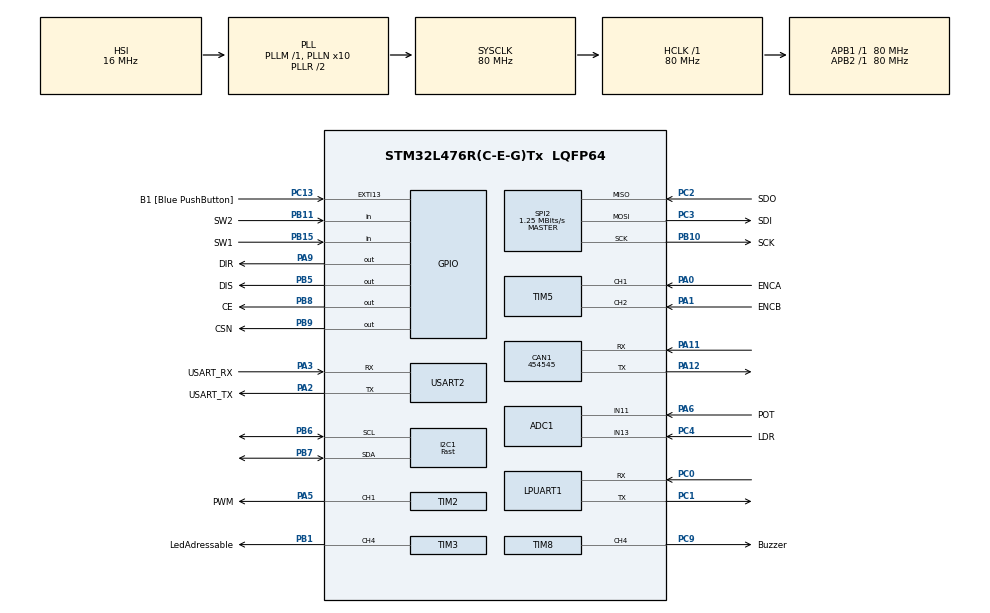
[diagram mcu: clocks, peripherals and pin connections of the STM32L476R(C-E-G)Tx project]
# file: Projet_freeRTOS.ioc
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ADC1.Channel-0\#ChannelRegularConversion=ADC_CHANNEL_11
ADC1.Channel-1\#ChannelRegularConversion=ADC_CHANNEL_13
ADC1.EOCSelection=ADC_EOC_SINGLE_CONV
ADC1.NbrOfConversion=2
ADC1.NbrOfConversionFlag=1
ADC1.OffsetNumber-0\#ChannelRegularConversion=ADC_OFFSET_NONE
ADC1.OffsetNumber-1\#ChannelRegularConversion=ADC_OFFSET_NONE
ADC1.Rank-0\#ChannelRegularConversion=1
ADC1.Rank-1\#ChannelRegularConversion=2
ADC1.SamplingTime-0\#ChannelRegularConversion=ADC_SAMPLETIME_47CYCLES_5
ADC1.SamplingTime-1\#ChannelRegularConversion=ADC_SAMPLETIME_47CYCLES_5
ADC1.master=1
CAN1.BS1=CAN_BS1_6TQ
CAN1.BS2=CAN_BS2_4TQ
CAN1.CalculateBaudRate=454545
CAN1.CalculateTimeBit=2200
CAN1.CalculateTimeQuantum=200.0
Dma.Request0=TIM3_CH4/UP
Dma.TIM3_CH4/UP.0.Direction=DMA_MEMORY_TO_PERIPH
Dma.TIM3_CH4/UP.0.Instance=DMA1_Channel3
Dma.TIM3_CH4/UP.0.MemDataAlignment=DMA_MDATAALIGN_HALFWORD
Dma.TIM3_CH4/UP.0.MemInc=DMA_MINC_ENABLE
Dma.TIM3_CH4/UP.0.Mode=DMA_NORMAL
Dma.TIM3_CH4/UP.0.PeriphDataAlignment=DMA_PDATAALIGN_HALFWORD
Dma.TIM3_CH4/UP.0.PeriphInc=DMA_PINC_DISABLE
Dma.TIM3_CH4/UP.0.Priority=DMA_PRIORITY_LOW
FREERTOS.INCLUDE_vTaskDelayUntil=1
FREERTOS.Tasks01=defaultTask,0,128,StartDefaultTask,Default,NULL,Dynamic,NULL,NULL
FREERTOS.configMAX_PRIORITIES=16
FREERTOS.configTOTAL_HEAP_SIZE=35000
FREERTOS.configUSE_IDLE_HOOK=1
FREERTOS.configUSE_NEWLIB_REENTRANT=1
I2C1.I2C_Speed_Mode=I2C_Fast
I2C1.Timing=0x00F12981
Mcu.Family=STM32L4
Mcu.Name=STM32L476R(C-E-G)Tx
Mcu.Package=LQFP64
NVIC.ADC1_2_IRQn=true\:5\:0\:false\:false\:true\:true\:true\:true\:true
NVIC.DMA1_Channel3_IRQn=true\:5\:0\:false\:false\:true\:true\:false\:true\:true
NVIC.PriorityGroup=NVIC_PRIORITYGROUP_4
NVIC.TIM6_DAC_IRQn=true\:15\:0\:false\:false\:true\:false\:false\:true\:true
NVIC.TimeBase=TIM6_DAC_IRQn
NVIC.TimeBaseIP=TIM6
PA0.GPIO_Label=ENCA
PA0.Signal=S_TIM5_CH1
PA1.GPIO_Label=ENCB
PA1.Signal=S_TIM5_CH2
PA11.Mode=CAN_Activate
PA11.Signal=CAN1_RX
PA12.Mode=CAN_Activate
PA12.Signal=CAN1_TX
PA13\ (JTMS-SWDIO).GPIO_Label=TMS
PA13\ (JTMS-SWDIO).Mode=Serial_Wire
PA13\ (JTMS-SWDIO).Signal=SYS_JTMS-SWDIO
PA14\ (JTCK-SWCLK).GPIO_Label=TCK
PA14\ (JTCK-SWCLK).Mode=Serial_Wire
PA14\ (JTCK-SWCLK).Signal=SYS_JTCK-SWCLK
PA2.GPIO_Label=USART_TX
PA2.GPIO_Mode=GPIO_MODE_AF_PP
PA2.GPIO_PuPd=GPIO_NOPULL
PA2.GPIO_Speed=GPIO_SPEED_FREQ_VERY_HIGH
PA2.Mode=Asynchronous
PA2.Signal=USART2_TX
PA3.GPIO_Label=USART_RX
PA3.GPIO_Mode=GPIO_MODE_AF_PP
PA3.GPIO_PuPd=GPIO_NOPULL
PA3.GPIO_Speed=GPIO_SPEED_FREQ_VERY_HIGH
PA3.Mode=Asynchronous
PA3.Signal=USART2_RX
PA5.GPIO_Label=PWM
PA5.Signal=S_TIM2_CH1
PA6.GPIO_Label=POT
PA6.Signal=ADCx_IN11
PA9.GPIO_Label=DIR
PA9.Signal=GPIO_Output
PB1.GPIO_Label=LedAdressable
PB1.Signal=S_TIM3_CH4
PB10.GPIO_Label=SCK
PB10.Mode=Full_Duplex_Master
PB10.Signal=SPI2_SCK
PB11.GPIO_Label=SW2
PB11.Signal=GPIO_Input
PB15.GPIO_Label=SW1
PB15.Signal=GPIO_Input
PB3\ (JTDO-TRACESWO).GPIO_Label=SWO
PB3\ (JTDO-TRACESWO).Signal=SYS_JTDO-SWO
PB5.GPIO_Label=DIS
PB5.Signal=GPIO_Output
PB6.Mode=I2C
PB6.Signal=I2C1_SCL
PB7.Mode=I2C
PB7.Signal=I2C1_SDA
PB8.GPIO_Label=CE
PB8.Signal=GPIO_Output
PB9.GPIO_Label=CSN
PB9.Signal=GPIO_Output
PC0.Mode=Asynchronous
PC0.Signal=LPUART1_RX
PC1.Mode=Asynchronous
PC1.Signal=LPUART1_TX
PC13.GPIO_Label=B1 [Blue PushButton]
PC13.GPIO_ModeDefaultEXTI=GPIO_MODE_IT_FALLING
PC13.GPIO_PuPd=GPIO_NOPULL
PC13.Signal=GPXTI13
PC14-OSC32_IN\ (PC14).Mode=LSE-External-Oscillator
PC14-OSC32_IN\ (PC14).Signal=RCC_OSC32_IN
PC15-OSC32_OUT\ (PC15).Mode=LSE-External-Oscillator
PC15-OSC32_OUT\ (PC15).Signal=RCC_OSC32_OUT
PC2.GPIO_Label=SDO
PC2.Mode=Full_Duplex_Master
PC2.Signal=SPI2_MISO
PC3.GPIO_Label=SDI
PC3.Mode=Full_Duplex_Master
PC3.Signal=SPI2_MOSI
PC4.GPIO_Label=LDR
PC4.Signal=ADCx_IN13
PC9.GPIO_Label=Buzzer
PC9.Signal=S_TIM8_CH4
PH0-OSC_IN\ (PH0).Signal=RCC_OSC_IN
PH1-OSC_OUT\ (PH1).Signal=RCC_OSC_OUT
ProjectManager.HeapSize=0x200
ProjectManager.StackSize=0x400
ProjectManager.TargetToolchain=STM32CubeIDE
RCC.ADCFreq_Value=64000000
RCC.AHBFreq_Value=80000000
RCC.APB1Freq_Value=80000000
RCC.APB1TimFreq_Value=80000000
RCC.APB2Freq_Value=80000000
RCC.APB2TimFreq_Value=80000000
RCC.CortexFreq_Value=80000000
RCC.HCLKFreq_Value=80000000
RCC.HSE_VALUE=8000000
RCC.HSI_VALUE=16000000
RCC.MSI_VALUE=4000000
RCC.PLLN=10
RCC.PLLSourceVirtual=RCC_PLLSOURCE_HSI
RCC.PREFETCH_ENABLE=1
RCC.SYSCLKFreq_VALUE=80000000
RCC.SYSCLKSource=RCC_SYSCLKSOURCE_PLLCLK
RCC.USBFreq_Value=64000000
RCC.VCOOutputFreq_Value=160000000
SH.ADCx_IN11.0=ADC1_IN11,IN11-Single-Ended
SH.ADCx_IN13.0=ADC1_IN13,IN13-Single-Ended
SH.S_TIM2_CH1.0=TIM2_CH1,PWM Generation1 CH1
SH.S_TIM3_CH4.0=TIM3_CH4,PWM Generation4 CH4
SH.S_TIM5_CH1.0=TIM5_CH1,Encoder_Interface
SH.S_TIM5_CH2.0=TIM5_CH2,Encoder_Interface
SH.S_TIM8_CH4.0=TIM8_CH4,PWM Generation4 CH4
SPI2.BaudRatePrescaler=SPI_BAUDRATEPRESCALER_64
SPI2.CLKPhase=SPI_PHASE_2EDGE
SPI2.CalculateBaudRate=1.25 MBits/s
SPI2.DataSize=SPI_DATASIZE_8BIT
SPI2.Direction=SPI_DIRECTION_2LINES
SPI2.Mode=SPI_MODE_MASTER
SPI2.VirtualType=VM_MASTER
TIM2.Channel-PWM\ Generation1\ CH1=TIM_CHANNEL_1
TIM2.Period=3999
TIM3.Channel-PWM\ Generation4\ CH4=TIM_CHANNEL_4
TIM3.Period=99
TIM5.EncoderMode=TIM_ENCODERMODE_TI12
TIM8.Channel-PWM\ Generation4\ CH4=TIM_CHANNEL_4
TIM8.Period=65535
TIM8.Prescaler=79
USART2.VirtualMode-Asynchronous=VM_ASYNC
VP_FREERTOS_VS_CMSIS_V1.Mode=CMSIS_V1
VP_SYS_VS_tim6.Mode=TIM6
VP_TIM3_VS_ClockSourceINT.Mode=Internal
VP_TIM8_VS_ClockSourceINT.Mode=Internal
board=NUCLEO-L476RG

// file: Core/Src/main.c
/* USER CODE BEGIN Header */
/**
 ******************************************************************************
 * @file           : main.c
 * @brief          : Main program body
 ******************************************************************************
 * @attention
 *
 * Copyright (c) 2026 STMicroelectronics.
 * All rights reserved.
 *
 * This software is licensed under terms that can be found in the LICENSE file
 * in the root directory of this software component.
 * If no LICENSE file comes with this software, it is provided AS-IS.
 *
 ******************************************************************************
 */
/* USER CODE END Header */
#include "main.h"
#include "cmsis_os.h"

/* USER CODE BEGIN Includes */
#include <stdio.h>
#include <stdlib.h>
#include "ssd1306.h"
#include <stdbool.h>

#include <string.h>
#include "vl53l1_api.h"

#include "ssd1306_fonts.h"
#include "app_rtos.h"
/* USER CODE END Includes */

ADC_HandleTypeDef hadc1;

CAN_HandleTypeDef hcan1;

I2C_HandleTypeDef hi2c1;

UART_HandleTypeDef hlpuart1;
UART_HandleTypeDef huart2;

SPI_HandleTypeDef hspi2;

TIM_HandleTypeDef htim2;
TIM_HandleTypeDef htim3;
TIM_HandleTypeDef htim5;
TIM_HandleTypeDef htim8;
DMA_HandleTypeDef hdma_tim3_ch4_up;

osThreadId defaultTaskHandle;

void SystemClock_Config(void);
static void MX_GPIO_Init(void);
static void MX_DMA_Init(void);
static void MX_USART2_UART_Init(void);
static void MX_I2C1_Init(void);
static void MX_ADC1_Init(void);
static void MX_CAN1_Init(void);
static void MX_LPUART1_UART_Init(void);
static void MX_SPI2_Init(void);
static void MX_TIM2_Init(void);
static void MX_TIM3_Init(void);
static void MX_TIM5_Init(void);
static void MX_TIM8_Init(void);
void StartDefaultTask(void const * argument);

int main(void)
{

	/* MCU Configuration--------------------------------------------------------*/

	/* Reset of all peripherals, Initializes the Flash interface and the Systick. */
	HAL_Init();

	/* Configure the system clock */
	SystemClock_Config();

	/* Initialize all configured peripherals */
	MX_GPIO_Init();
	MX_DMA_Init();
	MX_USART2_UART_Init();
	MX_I2C1_Init();
	MX_ADC1_Init();
	MX_CAN1_Init();
	MX_LPUART1_UART_Init();
	MX_SPI2_Init();
	MX_TIM2_Init();
	MX_TIM3_Init();
	MX_TIM5_Init();
	MX_TIM8_Init();
	/* USER CODE BEGIN 2 */

	HAL_ADCEx_Calibration_Start(&hadc1, ADC_SINGLE_ENDED);
	HAL_TIM_PWM_Start(&htim2, TIM_CHANNEL_1);                   // Lancement ventilateur (PA5)
	HAL_TIM_Encoder_Start(&htim5, TIM_CHANNEL_ALL);             // Lancement encodeur
	HAL_GPIO_WritePin(DIS_GPIO_Port, DIS_Pin, GPIO_PIN_SET);    // moteur désactivé au départ
	// moteur désactivé au départ
	HAL_UART_Receive_IT(&hlpuart1, (uint8_t *) &bluetoothChar, 1);

	//seuils de base
	consignes.seuil_temperature = 25;
	consignes.seuil_qa = 100;
	consignes.seuil_luminosite = 500;
	/* USER CODE END 2 */

	/* Create the thread(s) */
	/* definition and creation of defaultTask */
	osThreadDef(defaultTask, StartDefaultTask, osPriorityNormal, 0, 128);
	defaultTaskHandle = osThreadCreate(osThread(defaultTask), NULL);

	/* USER CODE BEGIN RTOS_THREADS */
	App_init();  // création des tâches (app_rtos.c)
	/* USER CODE END RTOS_THREADS */

	/* Start scheduler */
	osKernelStart();

	/* We should never get here as control is now taken by the scheduler */

	/* Infinite loop */
	while (1)
	{

	}
}

void SystemClock_Config(void)
{
	RCC_OscInitTypeDef RCC_OscInitStruct = {0};
	RCC_ClkInitTypeDef RCC_ClkInitStruct = {0};

	/** Configure the main internal regulator output voltage
	 */
	if (HAL_PWREx_ControlVoltageScaling(PWR_REGULATOR_VOLTAGE_SCALE1) != HAL_OK)
	{
		Error_Handler();
	}

	/** Initializes the RCC Oscillators according to the specified parameters
	 * in the RCC_OscInitTypeDef structure.
	 */
	RCC_OscInitStruct.OscillatorType = RCC_OSCILLATORTYPE_HSI;
	RCC_OscInitStruct.HSIState = RCC_HSI_ON;
	RCC_OscInitStruct.HSICalibrationValue = RCC_HSICALIBRATION_DEFAULT;
	RCC_OscInitStruct.PLL.PLLState = RCC_PLL_ON;
	RCC_OscInitStruct.PLL.PLLSource = RCC_PLLSOURCE_HSI;
	RCC_OscInitStruct.PLL.PLLM = 1;
	RCC_OscInitStruct.PLL.PLLN = 10;
	RCC_OscInitStruct.PLL.PLLP = RCC_PLLP_DIV7;
	RCC_OscInitStruct.PLL.PLLQ = RCC_PLLQ_DIV2;
	RCC_OscInitStruct.PLL.PLLR = RCC_PLLR_DIV2;
	if (HAL_RCC_OscConfig(&RCC_OscInitStruct) != HAL_OK)
	{
		Error_Handler();
	}

	/** Initializes the CPU, AHB and APB buses clocks
	 */
	RCC_ClkInitStruct.ClockType = RCC_CLOCKTYPE_HCLK|RCC_CLOCKTYPE_SYSCLK
			|RCC_CLOCKTYPE_PCLK1|RCC_CLOCKTYPE_PCLK2;
	RCC_ClkInitStruct.SYSCLKSource = RCC_SYSCLKSOURCE_PLLCLK;
	RCC_ClkInitStruct.AHBCLKDivider = RCC_SYSCLK_DIV1;
	RCC_ClkInitStruct.APB1CLKDivider = RCC_HCLK_DIV1;
	RCC_ClkInitStruct.APB2CLKDivider = RCC_HCLK_DIV1;

	if (HAL_RCC_ClockConfig(&RCC_ClkInitStruct, FLASH_LATENCY_4) != HAL_OK)
	{
		Error_Handler();
	}
}

static void MX_ADC1_Init(void)
{

	ADC_MultiModeTypeDef multimode = {0};
	ADC_ChannelConfTypeDef sConfig = {0};

	/** Common config
	 */
	hadc1.Instance = ADC1;
	hadc1.Init.ClockPrescaler = ADC_CLOCK_ASYNC_DIV1;
	hadc1.Init.Resolution = ADC_RESOLUTION_12B;
	hadc1.Init.DataAlign = ADC_DATAALIGN_RIGHT;
	hadc1.Init.ScanConvMode = ADC_SCAN_DISABLE;
	hadc1.Init.EOCSelection = ADC_EOC_SINGLE_CONV;
	hadc1.Init.LowPowerAutoWait = DISABLE;
	hadc1.Init.ContinuousConvMode = DISABLE;
	hadc1.Init.NbrOfConversion = 1;
	hadc1.Init.DiscontinuousConvMode = DISABLE;
	hadc1.Init.ExternalTrigConv = ADC_SOFTWARE_START;
	hadc1.Init.ExternalTrigConvEdge = ADC_EXTERNALTRIGCONVEDGE_NONE;
	hadc1.Init.DMAContinuousRequests = DISABLE;
	hadc1.Init.Overrun = ADC_OVR_DATA_PRESERVED;
	hadc1.Init.OversamplingMode = DISABLE;
	if (HAL_ADC_Init(&hadc1) != HAL_OK)
	{
		Error_Handler();
	}

	/** Configure the ADC multi-mode
	 */
	multimode.Mode = ADC_MODE_INDEPENDENT;
	if (HAL_ADCEx_MultiModeConfigChannel(&hadc1, &multimode) != HAL_OK)
	{
		Error_Handler();
	}

	/** Configure Regular Channel
	 */
	sConfig.Channel = ADC_CHANNEL_13;
	sConfig.Rank = ADC_REGULAR_RANK_1;
	sConfig.SamplingTime = ADC_SAMPLETIME_2CYCLES_5;
	sConfig.SingleDiff = ADC_SINGLE_ENDED;
	sConfig.OffsetNumber = ADC_OFFSET_NONE;
	sConfig.Offset = 0;
	if (HAL_ADC_ConfigChannel(&hadc1, &sConfig) != HAL_OK)
	{
		Error_Handler();
	}

}

static void MX_CAN1_Init(void)
{

	hcan1.Instance = CAN1;
	hcan1.Init.Prescaler = 16;
	hcan1.Init.Mode = CAN_MODE_NORMAL;
	hcan1.Init.SyncJumpWidth = CAN_SJW_1TQ;
	hcan1.Init.TimeSeg1 = CAN_BS1_7TQ;
	hcan1.Init.TimeSeg2 = CAN_BS2_2TQ;
	hcan1.Init.TimeTriggeredMode = DISABLE;
	hcan1.Init.AutoBusOff = DISABLE;
	hcan1.Init.AutoWakeUp = DISABLE;
	hcan1.Init.AutoRetransmission = DISABLE;
	hcan1.Init.ReceiveFifoLocked = DISABLE;
	hcan1.Init.TransmitFifoPriority = DISABLE;
	if (HAL_CAN_Init(&hcan1) != HAL_OK)
	{
		Error_Handler();
	}

}

static void MX_I2C1_Init(void)
{

	hi2c1.Instance = I2C1;
	hi2c1.Init.Timing = 0x00F12981;
	hi2c1.Init.OwnAddress1 = 0;
	hi2c1.Init.AddressingMode = I2C_ADDRESSINGMODE_7BIT;
	hi2c1.Init.DualAddressMode = I2C_DUALADDRESS_DISABLE;
	hi2c1.Init.OwnAddress2 = 0;
	hi2c1.Init.OwnAddress2Masks = I2C_OA2_NOMASK;
	hi2c1.Init.GeneralCallMode = I2C_GENERALCALL_DISABLE;
	hi2c1.Init.NoStretchMode = I2C_NOSTRETCH_DISABLE;
	if (HAL_I2C_Init(&hi2c1) != HAL_OK)
	{
		Error_Handler();
	}

	/** Configure Analogue filter
	 */
	if (HAL_I2CEx_ConfigAnalogFilter(&hi2c1, I2C_ANALOGFILTER_ENABLE) != HAL_OK)
	{
		Error_Handler();
	}

	/** Configure Digital filter
	 */
	if (HAL_I2CEx_ConfigDigitalFilter(&hi2c1, 0) != HAL_OK)
	{
		Error_Handler();
	}

}

static void MX_LPUART1_UART_Init(void)
{

	hlpuart1.Instance = LPUART1;
	hlpuart1.Init.BaudRate = 9600;
	hlpuart1.Init.WordLength = UART_WORDLENGTH_8B;
	hlpuart1.Init.StopBits = UART_STOPBITS_1;
	hlpuart1.Init.Parity = UART_PARITY_NONE;
	hlpuart1.Init.Mode = UART_MODE_TX_RX;
	hlpuart1.Init.HwFlowCtl = UART_HWCONTROL_NONE;
	hlpuart1.Init.OneBitSampling = UART_ONE_BIT_SAMPLE_DISABLE;
	hlpuart1.AdvancedInit.AdvFeatureInit = UART_ADVFEATURE_NO_INIT;
	if (HAL_UART_Init(&hlpuart1) != HAL_OK)
	{
		Error_Handler();
	}

}

static void MX_USART2_UART_Init(void)
{

	huart2.Instance = USART2;
	huart2.Init.BaudRate = 115200;
	huart2.Init.WordLength = UART_WORDLENGTH_8B;
	huart2.Init.StopBits = UART_STOPBITS_1;
	huart2.Init.Parity = UART_PARITY_NONE;
	huart2.Init.Mode = UART_MODE_TX_RX;
	huart2.Init.HwFlowCtl = UART_HWCONTROL_NONE;
	huart2.Init.OverSampling = UART_OVERSAMPLING_16;
	huart2.Init.OneBitSampling = UART_ONE_BIT_SAMPLE_DISABLE;
	huart2.AdvancedInit.AdvFeatureInit = UART_ADVFEATURE_NO_INIT;
	if (HAL_UART_Init(&huart2) != HAL_OK)
	{
		Error_Handler();
	}

}

static void MX_SPI2_Init(void)
{

	/* SPI2 parameter configuration*/
	hspi2.Instance = SPI2;
	hspi2.Init.Mode = SPI_MODE_MASTER;
	hspi2.Init.Direction = SPI_DIRECTION_2LINES;
	hspi2.Init.DataSize = SPI_DATASIZE_8BIT;
	hspi2.Init.CLKPolarity = SPI_POLARITY_LOW;
	hspi2.Init.CLKPhase = SPI_PHASE_2EDGE;
	hspi2.Init.NSS = SPI_NSS_SOFT;
	hspi2.Init.BaudRatePrescaler = SPI_BAUDRATEPRESCALER_64;
	hspi2.Init.FirstBit = SPI_FIRSTBIT_MSB;
	hspi2.Init.TIMode = SPI_TIMODE_DISABLE;
	hspi2.Init.CRCCalculation = SPI_CRCCALCULATION_DISABLE;
	hspi2.Init.CRCPolynomial = 7;
	hspi2.Init.CRCLength = SPI_CRC_LENGTH_DATASIZE;
	hspi2.Init.NSSPMode = SPI_NSS_PULSE_DISABLE;
	if (HAL_SPI_Init(&hspi2) != HAL_OK)
	{
		Error_Handler();
	}

}

static void MX_TIM2_Init(void)
{

	TIM_MasterConfigTypeDef sMasterConfig = {0};
	TIM_OC_InitTypeDef sConfigOC = {0};

	htim2.Instance = TIM2;
	htim2.Init.Prescaler = 0;
	htim2.Init.CounterMode = TIM_COUNTERMODE_UP;
	htim2.Init.Period = 3999;
	htim2.Init.ClockDivision = TIM_CLOCKDIVISION_DIV1;
	htim2.Init.AutoReloadPreload = TIM_AUTORELOAD_PRELOAD_DISABLE;
	if (HAL_TIM_PWM_Init(&htim2) != HAL_OK)
	{
		Error_Handler();
	}
	sMasterConfig.MasterOutputTrigger = TIM_TRGO_RESET;
	sMasterConfig.MasterSlaveMode = TIM_MASTERSLAVEMODE_DISABLE;
	if (HAL_TIMEx_MasterConfigSynchronization(&htim2, &sMasterConfig) != HAL_OK)
	{
		Error_Handler();
	}
	sConfigOC.OCMode = TIM_OCMODE_PWM1;
	sConfigOC.Pulse = 0;
	sConfigOC.OCPolarity = TIM_OCPOLARITY_HIGH;
	sConfigOC.OCFastMode = TIM_OCFAST_DISABLE;
	if (HAL_TIM_PWM_ConfigChannel(&htim2, &sConfigOC, TIM_CHANNEL_1) != HAL_OK)
	{
		Error_Handler();
	}
	HAL_TIM_MspPostInit(&htim2);

}

static void MX_TIM3_Init(void)
{

	TIM_ClockConfigTypeDef sClockSourceConfig = {0};
	TIM_MasterConfigTypeDef sMasterConfig = {0};
	TIM_OC_InitTypeDef sConfigOC = {0};

	htim3.Instance = TIM3;
	htim3.Init.Prescaler = 0;
	htim3.Init.CounterMode = TIM_COUNTERMODE_UP;
	htim3.Init.Period = 99;
	htim3.Init.ClockDivision = TIM_CLOCKDIVISION_DIV1;
	htim3.Init.AutoReloadPreload = TIM_AUTORELOAD_PRELOAD_DISABLE;
	if (HAL_TIM_Base_Init(&htim3) != HAL_OK)
	{
		Error_Handler();
	}
	sClockSourceConfig.ClockSource = TIM_CLOCKSOURCE_INTERNAL;
	if (HAL_TIM_ConfigClockSource(&htim3, &sClockSourceConfig) != HAL_OK)
	{
		Error_Handler();
	}
	if (HAL_TIM_PWM_Init(&htim3) != HAL_OK)
	{
		Error_Handler();
	}
	sMasterConfig.MasterOutputTrigger = TIM_TRGO_RESET;
	sMasterConfig.MasterSlaveMode = TIM_MASTERSLAVEMODE_DISABLE;
	if (HAL_TIMEx_MasterConfigSynchronization(&htim3, &sMasterConfig) != HAL_OK)
	{
		Error_Handler();
	}
	sConfigOC.OCMode = TIM_OCMODE_PWM1;
	sConfigOC.Pulse = 0;
	sConfigOC.OCPolarity = TIM_OCPOLARITY_HIGH;
	sConfigOC.OCFastMode = TIM_OCFAST_DISABLE;
	if (HAL_TIM_PWM_ConfigChannel(&htim3, &sConfigOC, TIM_CHANNEL_4) != HAL_OK)
	{
		Error_Handler();
	}
	HAL_TIM_MspPostInit(&htim3);

}

static void MX_TIM5_Init(void)
{

	TIM_Encoder_InitTypeDef sConfig = {0};
	TIM_MasterConfigTypeDef sMasterConfig = {0};

	htim5.Instance = TIM5;
	htim5.Init.Prescaler = 0;
	htim5.Init.CounterMode = TIM_COUNTERMODE_UP;
	htim5.Init.Period = 4294967295;
	htim5.Init.ClockDivision = TIM_CLOCKDIVISION_DIV1;
	htim5.Init.AutoReloadPreload = TIM_AUTORELOAD_PRELOAD_DISABLE;
	sConfig.EncoderMode = TIM_ENCODERMODE_TI1;
	sConfig.IC1Polarity = TIM_ICPOLARITY_RISING;
	sConfig.IC1Selection = TIM_ICSELECTION_DIRECTTI;
	sConfig.IC1Prescaler = TIM_ICPSC_DIV1;
	sConfig.IC1Filter = 0;
	sConfig.IC2Polarity = TIM_ICPOLARITY_RISING;
	sConfig.IC2Selection = TIM_ICSELECTION_DIRECTTI;
	sConfig.IC2Prescaler = TIM_ICPSC_DIV1;
	sConfig.IC2Filter = 0;
	if (HAL_TIM_Encoder_Init(&htim5, &sConfig) != HAL_OK)
	{
		Error_Handler();
	}
	sMasterConfig.MasterOutputTrigger = TIM_TRGO_RESET;
	sMasterConfig.MasterSlaveMode = TIM_MASTERSLAVEMODE_DISABLE;
	if (HAL_TIMEx_MasterConfigSynchronization(&htim5, &sMasterConfig) != HAL_OK)
	{
		Error_Handler();
	}

}

static void MX_TIM8_Init(void)
{

	TIM_ClockConfigTypeDef sClockSourceConfig = {0};
	TIM_MasterConfigTypeDef sMasterConfig = {0};
	TIM_OC_InitTypeDef sConfigOC = {0};
	TIM_BreakDeadTimeConfigTypeDef sBreakDeadTimeConfig = {0};

	htim8.Instance = TIM8;
	htim8.Init.Prescaler = 79;
	htim8.Init.CounterMode = TIM_COUNTERMODE_UP;
	htim8.Init.Period = 65535;
	htim8.Init.ClockDivision = TIM_CLOCKDIVISION_DIV1;
	htim8.Init.RepetitionCounter = 0;
	htim8.Init.AutoReloadPreload = TIM_AUTORELOAD_PRELOAD_DISABLE;
	if (HAL_TIM_Base_Init(&htim8) != HAL_OK)
	{
		Error_Handler();
	}
	sClockSourceConfig.ClockSource = TIM_CLOCKSOURCE_INTERNAL;
	if (HAL_TIM_ConfigClockSource(&htim8, &sClockSourceConfig) != HAL_OK)
	{
		Error_Handler();
	}
	if (HAL_TIM_PWM_Init(&htim8) != HAL_OK)
	{
		Error_Handler();
	}
	sMasterConfig.MasterOutputTrigger = TIM_TRGO_RESET;
	sMasterConfig.MasterOutputTrigger2 = TIM_TRGO2_RESET;
	sMasterConfig.MasterSlaveMode = TIM_MASTERSLAVEMODE_DISABLE;
	if (HAL_TIMEx_MasterConfigSynchronization(&htim8, &sMasterConfig) != HAL_OK)
	{
		Error_Handler();
	}
	sConfigOC.OCMode = TIM_OCMODE_PWM1;
	sConfigOC.Pulse = 0;
	sConfigOC.OCPolarity = TIM_OCPOLARITY_HIGH;
	sConfigOC.OCFastMode = TIM_OCFAST_DISABLE;
	sConfigOC.OCIdleState = TIM_OCIDLESTATE_RESET;
	sConfigOC.OCNIdleState = TIM_OCNIDLESTATE_RESET;
	if (HAL_TIM_PWM_ConfigChannel(&htim8, &sConfigOC, TIM_CHANNEL_4) != HAL_OK)
	{
		Error_Handler();
	}
	sBreakDeadTimeConfig.OffStateRunMode = TIM_OSSR_DISABLE;
	sBreakDeadTimeConfig.OffStateIDLEMode = TIM_OSSI_DISABLE;
	sBreakDeadTimeConfig.LockLevel = TIM_LOCKLEVEL_OFF;
	sBreakDeadTimeConfig.DeadTime = 0;
	sBreakDeadTimeConfig.BreakState = TIM_BREAK_DISABLE;
	sBreakDeadTimeConfig.BreakPolarity = TIM_BREAKPOLARITY_HIGH;
	sBreakDeadTimeConfig.BreakFilter = 0;
	sBreakDeadTimeConfig.Break2State = TIM_BREAK2_DISABLE;
	sBreakDeadTimeConfig.Break2Polarity = TIM_BREAK2POLARITY_HIGH;
	sBreakDeadTimeConfig.Break2Filter = 0;
	sBreakDeadTimeConfig.AutomaticOutput = TIM_AUTOMATICOUTPUT_DISABLE;
	if (HAL_TIMEx_ConfigBreakDeadTime(&htim8, &sBreakDeadTimeConfig) != HAL_OK)
	{
		Error_Handler();
	}
	HAL_TIM_MspPostInit(&htim8);

}

static void MX_DMA_Init(void)
{

	/* DMA controller clock enable */
	__HAL_RCC_DMA1_CLK_ENABLE();

	/* DMA interrupt init */
	/* DMA1_Channel3_IRQn interrupt configuration */
	HAL_NVIC_SetPriority(DMA1_Channel3_IRQn, 5, 0);
	HAL_NVIC_EnableIRQ(DMA1_Channel3_IRQn);

}

static void MX_GPIO_Init(void)
{
	GPIO_InitTypeDef GPIO_InitStruct = {0};

	/* GPIO Ports Clock Enable */
	__HAL_RCC_GPIOC_CLK_ENABLE();
	__HAL_RCC_GPIOH_CLK_ENABLE();
	__HAL_RCC_GPIOA_CLK_ENABLE();
	__HAL_RCC_GPIOB_CLK_ENABLE();

	/*Configure GPIO pin Output Level */
	HAL_GPIO_WritePin(GPIOH, SHUT1_Pin|SHUT2_Pin, GPIO_PIN_RESET);

	/*Configure GPIO pin Output Level */
	HAL_GPIO_WritePin(DIR_GPIO_Port, DIR_Pin, GPIO_PIN_RESET);

	/*Configure GPIO pin Output Level */
	HAL_GPIO_WritePin(GPIOB, DIS_Pin|CE_Pin|CSN_Pin, GPIO_PIN_RESET);

	/*Configure GPIO pin : B1_Pin */
	GPIO_InitStruct.Pin = B1_Pin;
	GPIO_InitStruct.Mode = GPIO_MODE_IT_FALLING;
	GPIO_InitStruct.Pull = GPIO_NOPULL;
	HAL_GPIO_Init(B1_GPIO_Port, &GPIO_InitStruct);

	/*Configure GPIO pins : SHUT1_Pin SHUT2_Pin */
	GPIO_InitStruct.Pin = SHUT1_Pin|SHUT2_Pin;
	GPIO_InitStruct.Mode = GPIO_MODE_OUTPUT_PP;
	GPIO_InitStruct.Pull = GPIO_NOPULL;
	GPIO_InitStruct.Speed = GPIO_SPEED_FREQ_LOW;
	HAL_GPIO_Init(GPIOH, &GPIO_InitStruct);

	/*Configure GPIO pin : SW2_Pin */
	GPIO_InitStruct.Pin = SW2_Pin;
	GPIO_InitStruct.Mode = GPIO_MODE_IT_RISING;
	GPIO_InitStruct.Pull = GPIO_NOPULL;
	HAL_GPIO_Init(SW2_GPIO_Port, &GPIO_InitStruct);

	/*Configure GPIO pin : DIR_Pin */
	GPIO_InitStruct.Pin = DIR_Pin;
	GPIO_InitStruct.Mode = GPIO_MODE_OUTPUT_PP;
	GPIO_InitStruct.Pull = GPIO_NOPULL;
	GPIO_InitStruct.Speed = GPIO_SPEED_FREQ_LOW;
	HAL_GPIO_Init(DIR_GPIO_Port, &GPIO_InitStruct);

	/*Configure GPIO pin : SW1_Pin */
	GPIO_InitStruct.Pin = SW1_Pin;
	GPIO_InitStruct.Mode = GPIO_MODE_IT_RISING;
	GPIO_InitStruct.Pull = GPIO_NOPULL;
	HAL_GPIO_Init(SW1_GPIO_Port, &GPIO_InitStruct);

	/*Configure GPIO pins : INTOF2_Pin INTOF1_Pin */
	GPIO_InitStruct.Pin = INTOF2_Pin|INTOF1_Pin;
	GPIO_InitStruct.Mode = GPIO_MODE_INPUT;
	GPIO_InitStruct.Pull = GPIO_NOPULL;
	HAL_GPIO_Init(GPIOC, &GPIO_InitStruct);

	/*Configure GPIO pins : DIS_Pin CE_Pin CSN_Pin */
	GPIO_InitStruct.Pin = DIS_Pin|CE_Pin|CSN_Pin;
	GPIO_InitStruct.Mode = GPIO_MODE_OUTPUT_PP;
	GPIO_InitStruct.Pull = GPIO_NOPULL;
	GPIO_InitStruct.Speed = GPIO_SPEED_FREQ_LOW;
	HAL_GPIO_Init(GPIOB, &GPIO_InitStruct);

	/* EXTI interrupt init*/
	HAL_NVIC_SetPriority(EXTI15_10_IRQn, 5, 0);
	HAL_NVIC_EnableIRQ(EXTI15_10_IRQn);

}

void StartDefaultTask(void const * argument)
{
	for(;;)
	{
		osDelay(1);
	}
}

void HAL_TIM_PeriodElapsedCallback(TIM_HandleTypeDef *htim)
{
	if (htim->Instance == TIM6)
	{
		HAL_IncTick();
	}
}

void Error_Handler(void)
{
	__disable_irq();
	while (1)
	{
	}
}
